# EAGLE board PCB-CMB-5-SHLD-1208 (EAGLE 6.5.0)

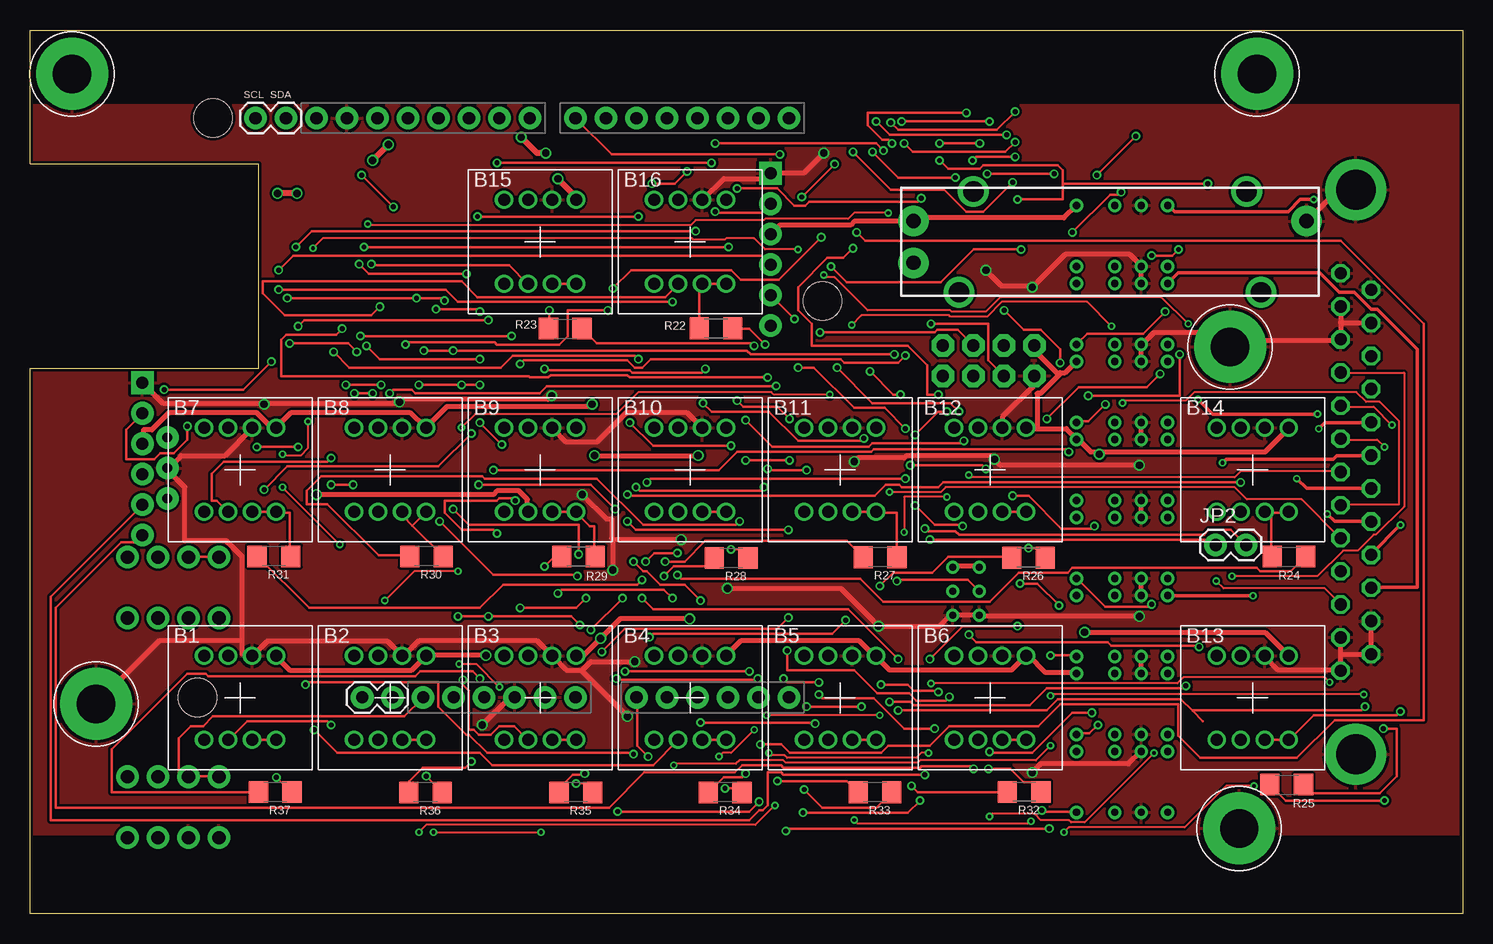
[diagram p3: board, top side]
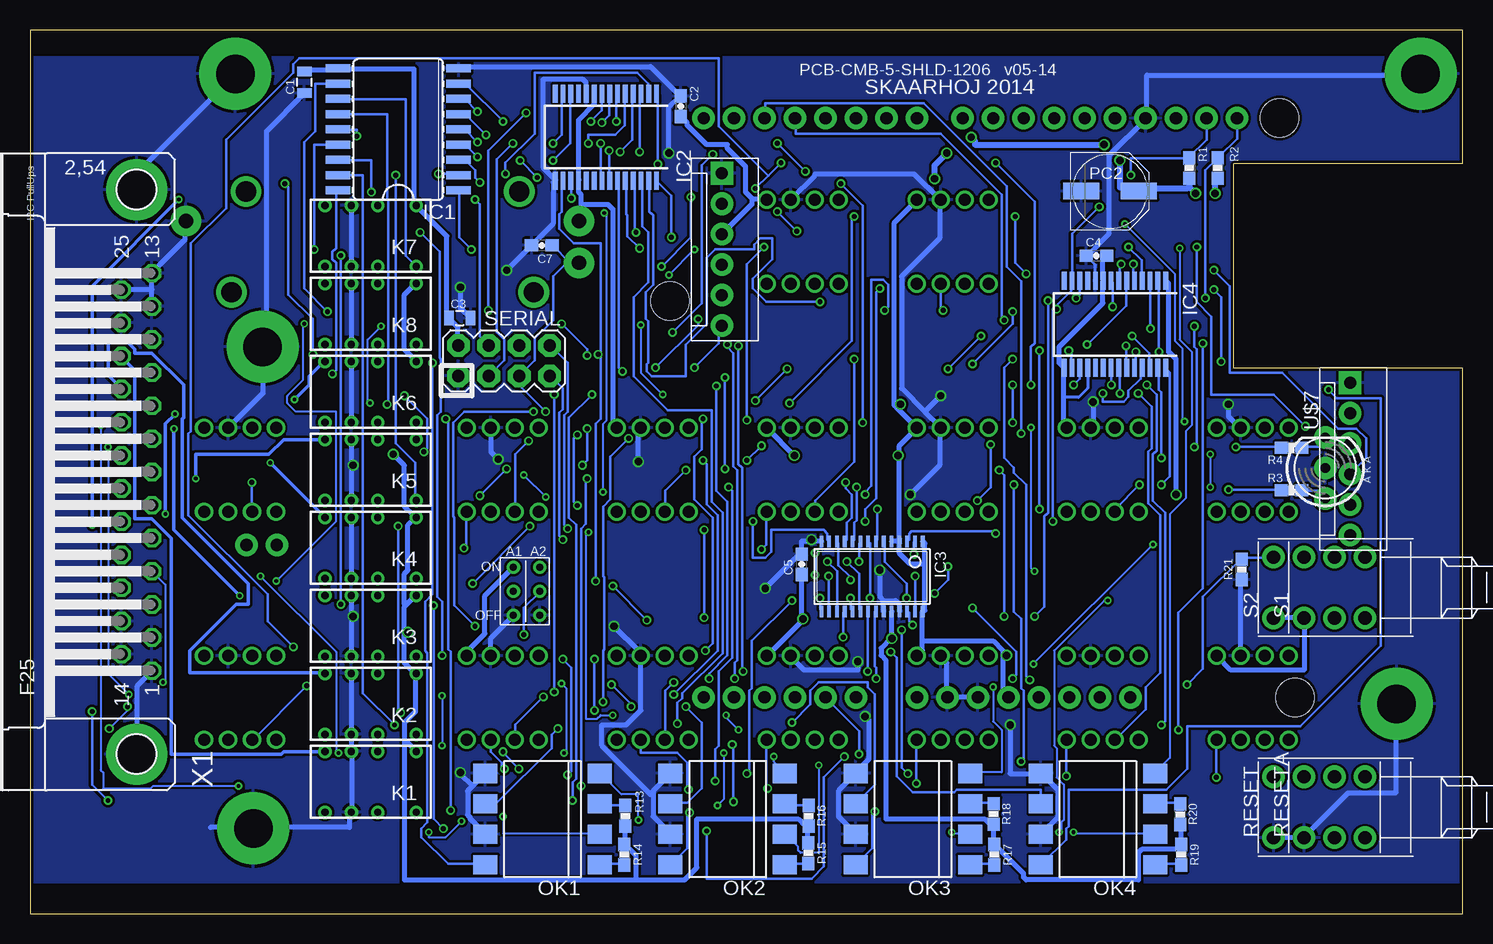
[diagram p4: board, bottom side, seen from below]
Size 119.38 x 73.66 mm. Coordinates in mm from the lower left corner, seen from the top.
Outline: 0,0 0,45.47 19.05,45.47 19.05,62.5 0,62.5 0,73.66 119.38,73.66 119.38,0 0,0
Copper layers (1*16): Top 0.035mm / dielectric 1.5mm / Bottom 0.035mm
Design rules "Fusion_eagle_rule_v1.1": minimum track width 6mil, minimum drill 12mil, track to track 6mil, track to pad 6mil, pad to pad 6mil, via to via 6mil, smd to smd 0mil, copper to edge 10mil, drill to drill 10mil, minimum pad ring 10mil, minimum via ring 6mil, stop-mask expansion 2mil, vias tented up to drill 100mil, thermal gap 10mil
Net classes: 0 default: width 0.203 mm, drill 0.406 mm, clearance 0.203 mm; 1 Power: width 0.508 mm, drill 0.61 mm, clearance 0.203 mm; 2 RELAY LINES: width 0.305 mm, clearance 0.203 mm; 3 INput lines: clearance 0.203 mm
Holes 3.2 mm at 66.04,51.07 15.24,66.31 13.97,18.05
tRestrict: area 0,0 to 120,6.5; area 0,67.5 to 120,74
bRestrict: area 0,71.5 to 120,74; area 0,0 to 120,2.5

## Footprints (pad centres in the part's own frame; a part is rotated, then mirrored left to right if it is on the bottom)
NKK-NP01 = drill 1: 1 1,3.5; 2 -1,-3.5; L1 3,-3.5; L2 1,-3.5; L3 -1,3.5; L4 -3,3.5; LC1 3,3.5; LC2 -3,-3.5
0805 = smd 0.8 x 1.2: 1 -0.9,0; 2 0.9,0
0603-CAP = smd 1.1 x 1: 1 -0.85,0; 2 0.85,0
DUEMILANOVE_VIAS = drill 1.016 pad 1.88: 3.3V 50.8,13.97; 5V 50.8,16.51; A0 50.8,29.21; A1 50.8,31.75; A2 50.8,34.29; A3 50.8,36.83; A4 50.8,39.37; A5 50.8,41.91; AREF 2.54,2.54; D2 2.54,36.83; D3 2.54,34.29; D4 2.54,31.75; D5 2.54,29.21; D6 2.54,26.67; D7 2.54,24.13; D8 2.54,20.32; D9 2.54,17.78; D10 2.54,15.24; D11 2.54,12.7; D12 2.54,10.16; D13 2.54,7.62; GND@0 50.8,19.05; GND@1 50.8,21.59; GND@2 2.54,5.08; RES 50.8,11.43; RX 2.54,41.91; TX 2.54,39.37; VIN 50.8,24.13
SO18W = smd 0.66 x 2.032: 1 -5.08,-5.029; 2 -3.81,-5.029; 3 -2.54,-5.029; 4 -1.27,-5.029; 5 0,-5.029; 6 1.27,-5.029; 7 2.54,-5.029; 8 3.81,-5.029; 9 5.08,-5.029; 10 5.08,5.029; 11 3.81,5.029; 12 2.54,5.029; 13 1.27,5.029; 14 0,5.029; 15 -1.27,5.029; 16 -2.54,5.029; 17 -3.81,5.029; 18 -5.08,5.029
SSOP28 = smd 0.4 x 1.5: 1 -4.225,-3.625; 2 -3.575,-3.625; 3 -2.925,-3.625; 4 -2.275,-3.625; 5 -1.625,-3.625; 6 -0.975,-3.625; 7 -0.325,-3.625; 8 0.325,-3.625; 9 0.975,-3.625; 10 1.625,-3.625; 11 2.275,-3.625; 12 2.925,-3.625; 13 3.575,-3.625; 14 4.225,-3.625; 15 4.225,3.625; 16 3.575,3.625; 17 2.925,3.625; 18 2.275,3.625; 19 1.625,3.625; 20 0.975,3.625; 21 0.325,3.625; 22 -0.325,3.625; 23 -0.975,3.625; 24 -1.625,3.625; 25 -2.275,3.625; 26 -2.925,3.625; 27 -3.575,3.625; 28 -4.225,3.625
TSSOP28 = smd 0.305 x 0.991: 1 -4.225,-2.918; 2 -3.575,-2.918; 3 -2.925,-2.918; 4 -2.275,-2.918; 5 -1.625,-2.918; 6 -0.975,-2.918; 7 -0.325,-2.918; 8 0.325,-2.918; 9 0.975,-2.918; 10 1.625,-2.918; 11 2.275,-2.918; 12 2.925,-2.918; 13 3.575,-2.918; 14 4.225,-2.918; 15 4.225,2.918; 16 3.575,2.918; 17 2.925,2.918; 18 2.275,2.918; 19 1.625,2.918; 20 0.975,2.918; 21 0.325,2.918; 22 -0.325,2.918; 23 -0.975,2.918; 24 -1.625,2.918; 25 -2.275,2.918; 26 -2.925,2.918; 27 -3.575,2.918; 28 -4.225,2.918
1X02 = drill 1.016 pad 1.88: 1 0,0; 2 2.54,0
MOLEX-1X6 = drill 1.016 pad 1.88 square: 1 0,0 | drill 1.016 pad 1.88: 2 2.54,0; 3 5.08,0; 4 7.62,0; 5 10.16,0; 6 12.7,0
DS2Y = drill 0.6: 1 1.2,0.46; 16 1.2,5.54; O1 4.4,0.46; O2 4.4,5.54; P1 6.6,0.46; P2 6.6,5.54; S1 8.8,0.46; S2 8.8,5.54
DIL8-SMD = smd 1.6 x 2: 1 -3.81,-4.77; 2 -1.27,-4.77; 3 1.27,-4.77; 4 3.81,-4.77; 5 3.81,4.77; 6 1.27,4.77; 7 -1.27,4.77; 8 -3.81,4.77
PANASONIC_D = smd 3 x 1.4: + 2.4,0; - -2.4,0
SLIDER20 = drill 1.194 pad 2.54: 1 -16.383,1.74; 2A -16.383,-1.74; 3 16.383,1.74 | drill 1.702: P$1 -11.392,4.191; P$2 11.392,4.191; P$3 12.598,-4.191; P$4 -12.598,-4.191
0603-RES = smd 1.1 x 1: 1 -0.85,0; 2 0.85,0
1206 = smd 1.6 x 1.8: 1 -1.4,0; 2 1.4,0
PUSHBUTTON = drill 1.1 pad 1.88: 1 2.54,2.54; 2 2.54,-2.54; 3 -2.54,2.54; 4 -2.54,-2.54
2X4 = drill 1.016 pad 1.88 octagon: 1 -3.81,-1.27; 2 -3.81,1.27; 3 -1.27,-1.27; 4 -1.27,1.27; 5 1.27,-1.27; 6 1.27,1.27; 7 3.81,-1.27; 8 3.81,1.27
3.2MMPAD6MM = drill 3.2 pad 6: P$1 0,0
LED5MM-BICOLOR = drill 0.813 pad 1.88: A2 2.54,0; A3 -2.54,0; K1 0,0
2BITADDR = drill 0.6: A1 0,0; A2 2.2,0; H2 0,2; H3 2.2,2; L2 0,-2; L3 2.2,-2
F25HP = drill 1.016 octagon: 1 -16.561,-1.27; 2 -13.792,-1.27; 3 -11.049,-1.27; 4 -8.28,-1.27; 5 -5.512,-1.27; 6 -2.769,-1.27; 7 0,-1.27; 8 2.769,-1.27; 9 5.512,-1.27; 10 8.28,-1.27; 11 11.049,-1.27; 12 13.792,-1.27; 13 16.561,-1.27; 14 -15.189,1.27; 15 -12.421,1.27; 16 -9.652,1.27; 17 -6.909,1.27; 18 -4.14,1.27; 19 -1.372,1.27; 20 1.372,1.27; 21 4.14,1.27; 22 6.909,1.27; 23 9.652,1.27; 24 12.421,1.27; 25 15.189,1.27 | drill 3.302 pad 5.08: G1 -23.52,0; G2 23.52,0

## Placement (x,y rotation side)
B1  NKK-NP01-SINGLECOLOR  [NKK-NP01]  17.5,18 0 top
B2  NKK-NP01-SINGLECOLOR  [NKK-NP01]  30,18 0 top
B3  NKK-NP01-SINGLECOLOR  [NKK-NP01]  42.5,18 0 top
B4  NKK-NP01-SINGLECOLOR  [NKK-NP01]  55,18 0 top
B5  NKK-NP01-SINGLECOLOR  [NKK-NP01]  67.5,18 0 top
B6  NKK-NP01-SINGLECOLOR  [NKK-NP01]  80,18 0 top
B7  NKK-NP01-SINGLECOLOR  [NKK-NP01]  17.5,37 0 top
B8  NKK-NP01-SINGLECOLOR  [NKK-NP01]  30,37 0 top
B9  NKK-NP01-SINGLECOLOR  [NKK-NP01]  42.5,37 0 top
B10  NKK-NP01-SINGLECOLOR  [NKK-NP01]  55,37 0 top
B11  NKK-NP01-SINGLECOLOR  [NKK-NP01]  67.5,37 0 top
B12  NKK-NP01-SINGLECOLOR  [NKK-NP01]  80,37 0 top
B13  NKK-NP01-SINGLECOLOR  [NKK-NP01]  101.88,18 0 top
B14  NKK-NP01-SINGLECOLOR  [NKK-NP01]  101.88,37 0 top
B15  NKK-NP01-SINGLECOLOR  [NKK-NP01]  42.5,56 0 top
B16  NKK-NP01-SINGLECOLOR  [NKK-NP01]  55,56 0 top
C1  100nF  [0805]  96.52,69.31 90 bottom
C2  100nF  [0603-CAP]  65.15,67.31 270 bottom
C3  10uF  [0805]  83.57,49.66 0 bottom
C4  100nF  [0603-CAP]  30.51,54.86 0 bottom
C5  100nF  [0603-CAP]  55.07,29.13 90 bottom
C7  10nF  [0603-CAP]  76.73,55.71 180 bottom
GND  ARDUINO_SHIELDNO_SILK  [DUEMILANOVE_VIAS]  21.34,68.85 270 top
IC1  ULN2803A  [SO18W]  88.7,65.38 90 bottom
IC2  MCP23017SS  [SSOP28]  71.39,64.73 180 bottom
IC3  PCA9685  [TSSOP28]  49.21,28.12 180 bottom
IC4  MCP23017SS  [SSOP28]  28.97,49.12 180 bottom
JP1  [1X02]  27.69,18.05 0 top
JP2  [1X02]  98.81,30.75 0 top
JP3  [MOLEX-1X6]  61.72,61.72 270 bottom
JP4  [1X02]  21.34,66.31 180 top
JP5  [MOLEX-1X6]  9.36,44.26 270 bottom
K1  RELAY5VIM03  [DS2Y]  86,14 180 bottom
K2  RELAY5VIM03  [DS2Y]  86,20.5 180 bottom
K3  RELAY5VIM03  [DS2Y]  86,27 180 bottom
K4  RELAY5VIM03  [DS2Y]  86,33.5 180 bottom
K5  RELAY5VIM03  [DS2Y]  86,40 180 bottom
K6  RELAY5VIM03  [DS2Y]  86,46.5 180 bottom
K7  RELAY5VIM03  [DS2Y]  86,59.5 180 bottom
K8  RELAY5VIM03  [DS2Y]  86,53 180 bottom
OK1  LTV826S  [DIL8-SMD]  76.67,7.9 90 bottom
OK2  LTV826S  [DIL8-SMD]  61.24,7.9 90 bottom
OK3  LTV826S  [DIL8-SMD]  45.81,7.9 90 bottom
OK4  LTV826S  [DIL8-SMD]  30.38,7.9 90 bottom
PC2  47u  [PANASONIC_D]  29.38,60.24 0 bottom
POT1  10K Linear  [SLIDER20]  90,56 0 top
R1  1K5  [0603-RES]  22.77,62.15 270 bottom
R2  1K5  [0603-RES]  20.4,62.15 270 bottom
R3  270  [0603-RES]  14.24,35.29 180 bottom
R4  270  [0603-RES]  14.24,38.83 180 bottom
R13  330R  [0603-RES]  69.76,8.18 90 bottom
R14  330R  [0603-RES]  69.86,4.93 270 bottom
R15  330R  [0603-RES]  54.53,5.06 270 bottom
R16  330R  [0603-RES]  54.47,8.18 90 bottom
R17  330R  [0603-RES]  39.03,4.93 270 bottom
R18  330R  [0603-RES]  39.06,8.32 90 bottom
R19  330R  [0603-RES]  23.46,4.93 270 bottom
R20  330R  [0603-RES]  23.52,8.3 90 bottom
R21  10K  [0603-RES]  18.41,28.72 90 bottom
R22  100R  [1206]  57.16,48.8 0 top
R23  100R  [1206]  44.61,48.77 0 top
R24  100R  [1206]  104.91,29.77 0 top
R25  100R  [1206]  104.72,10.77 0 top
R26  100R  [1206]  83.2,29.68 180 top
R27  100R  [1206]  70.84,29.72 180 top
R28  100R  [1206]  58.43,29.65 180 top
R29  100R  [1206]  45.71,29.78 180 top
R30  100R  [1206]  33.04,29.8 180 top
R31  100R  [1206]  20.32,29.8 180 top
R32  100R  [1206]  82.84,10.16 180 top
R33  100R  [1206]  70.41,10.14 180 top
R34  100R  [1206]  57.93,10.12 180 top
R35  100R  [1206]  45.48,10.12 180 top
R36  100R  [1206]  32.96,10.12 180 top
R37  100R  [1206]  20.43,10.15 180 top
RESET  [PUSHBUTTON]  13.21,8.89 90 bottom
RESETA  [PUSHBUTTON]  10.67,8.89 90 bottom
S1  [PUSHBUTTON]  10.67,27.19 90 bottom
S2  [PUSHBUTTON]  13.21,27.19 90 bottom
SERIAL  M04X2  [2X4]  79.88,46.1 0 bottom
U$4  GNDPAD6MM  [3.2MMPAD6MM]  100,47.25 0 top
U$7  LEDBICOLOR-AKA  [LED5MM-BICOLOR]  11.44,37.16 90 bottom
U$15  GNDPAD6MM  [3.2MMPAD6MM]  100.77,7.12 0 top
U$18  GNDPAD6MM  [3.2MMPAD6MM]  102.26,70 0 top
U$19  2BITADDR  [2BITADDR]  79.1,26.89 0 bottom
U$20  GNDPAD6MM  [3.2MMPAD6MM]  5.5,17.5 0 top
U$21  GNDPAD6MM  [3.2MMPAD6MM]  3.5,70 0 top
X1  DB25F  [F25HP]  110.49,36.83 90 bottom

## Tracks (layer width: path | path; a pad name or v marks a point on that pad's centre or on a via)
5V  (via drill 0.61)
  Top 0.406: JP5.3 9.45,39.22 9.45,40.34 10.16,40.34 11.58,41.76 18.9,41.76 20.12,40.54 20.32,40.54 B7.LC1 20.52,40.54 21.74,41.76 31.7,41.76 32.92,40.54 B8.LC1 33.12,40.64 34.75,42.27 46.63,42.27 v46.84,42.47 | B1.LC1 20.52,21.44 21.64,20.32 31.8,20.32 32.92,21.44 B2.LC1 33.12,21.54 v38,21.54 | B3.LC1 45.52,21.54 46.13,21.54 v47.55,22.96 49.17,24.59 v54.97,24.59 | v47.04,38.2 v55.68,38.2 | JP3.3 62.48,57.4 68.38,57.4 68.68,57.71 73.56,57.71 POT1.1 73.76,57.81 73.97,58.01 86.16,58.01 87.17,59.03 K7.1 | 83.92,40.44 83.01,40.44 B12.LC1 | 83.92,40.44 86.36,40.44 87.17,39.62 K5.1 87.38,39.52 88.39,38.51 89.1,38.51 | 89.1,38.51 102.92,38.51 104.85,40.44 B14.LC1 | 85.85,45.11 85.55,45.11 83.72,46.94 83.72,47.35 SERIAL.2 | 85.85,45.11 86.26,45.11 87.17,46.02 K6.1 | 83.92,40.44 83.92,43.38 84.23,43.38 85.85,45.01 85.85,45.11 | U$19.H3 76.91,28.96 79.05,28.96 U$19.H2 | B4.LC1 58.01,21.54 59.23,22.76 69.09,22.76 70.31,21.54 B5.LC1 70.51,21.44 71.63,20.32 81.79,20.32 82.91,21.44 B6.LC1 83.21,21.54 84.63,20.12 87.17,20.12 K2.1 | v87.88,23.47 102.92,23.47 104.85,21.54 B13.LC1 | v89.1,38.3 89.1,38.51
  Top 0.508: v22.25,60.05 v20.62,60.05 | v29.87,64.11 v28.55,62.79 | v40.95,64.72 42.27,63.4 v42.98,63.4 | v43.99,61.27 45.41,59.84 45.41,59.54 B15.LC1
  Bottom 0.254: IC4.18 31.24,43.81 32,43.05 33.22,43.05
  Bottom 0.406: C4.2 29.67,54.76 29.97,54.46 29.97,52.83 IC4.9 29.97,52.63 29.97,50.9 33.63,47.24 33.63,45.92 33.33,45.62 IC4.15 33.22,45.41 33.22,43.05 33.22,40.74 33.02,40.54 B8.LC1 | B1.LC1 20.42,21.44 19.3,20.32 13.21,20.32 S1.3 13.31,24.69 15.75,24.69 S2.3 | R20.1 23.47,7.42 23.47,5.79 R19.1 23.47,5.59 23.47,5.38 26.72,5.38 27.03,5.08 27.03,2.85 36.37,2.85 36.58,3.05 36.58,3.35 38.91,5.69 R17.1 39.12,5.79 39.12,7.42 R18.1 39.32,7.42 39.83,7.92 48.06,7.92 48.06,21.13 48.46,21.54 48.46,22.15 47.65,22.96 v47.55,22.96 47.55,25.2 IC3.24 | IC3.4 46.94,31.09 47.55,31.09 IC3.5 | 45.01,22.76 45.01,21.95 45.41,21.54 B3.LC1 | 45.01,22.76 45.01,25.2 IC3.28 44.81,25.3 44.81,29.16 | 44.81,29.16 44.81,30.89 44.91,30.99 IC3.1 | 44.81,29.16 46.02,29.16 46.94,30.07 46.94,30.89 IC3.4 | 46.94,38.2 46.94,31.29 IC3.4 | 46.94,38.2 46.94,39.01 45.52,40.44 B9.LC1 45.62,40.64 47.14,42.16 | v55.68,38.2 57.91,40.44 B10.LC1 | v47.04,38.2 46.94,38.2 | 47.14,42.16 47.35,42.37 47.35,57.61 45.52,59.44 B15.LC1 | 38.3,21.54 38.3,21.95 39.12,22.76 45.01,22.76 | 38.3,21.54 38.3,18.49 37.9,18.09 GND.5V | 38.3,21.54 v38,21.54 | 47.14,42.16 v46.84,42.47 | 59.13,59.54 59.74,60.15 59.74,62.28 61.27,63.8 61.27,64.11 62.99,64.11 64.62,65.73 64.62,65.94 65.13,66.45 C2.2 | 59.13,59.54 58.01,59.54 B16.LC1 | JP3.3 59.23,59.13 59.23,59.44 59.13,59.54 | 73.46,59.13 73.46,57.91 73.56,57.81 POT1.1 | 73.46,59.13 73.46,59.94 73.66,60.15 73.66,61.06 IC2.18 73.66,61.27 73.66,66.14 72.34,67.46 72.34,68.28 IC2.9 | 73.46,59.13 71.22,59.13 70.81,58.73 70.81,40.84 70.51,40.54 B11.LC1 | C1.2 96.52,70.31 93.78,70.31 93.78,70.41 IC1.10 93.57,70.41 87.38,70.41 87.38,59.13 K7.1 87.17,59.03 84.63,56.49 84.63,49.78 C3.1 84.43,49.58 83.72,48.87 83.72,47.45 SERIAL.2
  Bottom 0.406: K8.1 87.27,52.53 88.19,51.61 88.19,47.04 87.27,46.13 K6.1 | 55.07,24.59 55.07,24.38 57.91,21.54 B4.LC1 | 55.07,24.59 55.07,28.25 C5.1 | U$19.H2 79.15,28.85 81.48,26.52 81.48,23.37 82.91,21.95 82.91,21.54 B6.LC1 | R15.1 54.56,5.99 54.56,7.32 R16.1 54.76,7.32 55.37,7.92 63.8,7.92 63.8,3.86 64.82,2.85 68.89,2.85 | R13.1 69.8,7.32 69.8,5.79 R14.1 69.7,5.69 68.89,4.88 68.89,2.85 | 88.09,14.43 88.19,14.53 88.19,15.95 87.27,16.87 87.27,20.02 K2.1 87.38,20.12 88.19,20.93 88.19,23.47 | 88.09,14.43 K1.1 | 88.09,25.7 88.19,25.6 88.19,23.47 | 88.09,25.7 87.27,26.52 K3.1 | 88.09,25.7 88.19,25.81 88.19,28.35 87.88,28.65 87.88,32.41 87.27,33.02 K4.1 87.38,33.12 88.19,33.93 88.19,37.39 v89.1,38.3 | 88.19,23.47 v87.88,23.47 | 68.89,2.85 88.19,2.85 88.19,14.33 88.09,14.43 | v54.97,24.59 55.07,24.59
  Bottom 0.508: v20.62,60.05 20.62,61.06 20.42,61.27 R2.2 | 22.76,60.55 v22.25,60.05 | 22.76,60.55 22.76,61.27 R1.2 | 22.76,60.55 22.96,60.45 26.92,60.45 26.92,60.25 PC2.+ 27.13,60.55 28.55,60.55 v28.55,62.79 | v29.87,64.11 40.64,64.11 40.64,64.41 v40.95,64.72 | v42.98,63.4 43.99,62.38 v43.99,61.27
A1  (via drill 0.41)
  Top 0.203: v45.72,29.97 45.72,32.41 36.58,32.41 v35.26,33.73 | v32.82,46.94 v35.26,46.94 59.74,46.94 60.05,46.63 v72.03,46.63 | v72.24,27.74 72.34,27.84 78.13,27.84 79.05,26.92 U$19.A1
  Bottom 0.203: v45.72,29.97 45.72,30.99 IC3.2 | v35.26,46.94 v35.26,33.73 | v32.82,46.94 32.61,46.74 32.61,45.52 IC4.16 | 71.83,46.63 71.83,41.25 72.24,40.84 v72.24,27.74 | 71.83,46.63 71.83,55.88 74.07,55.88 75.29,57.1 75.29,58.32 75.08,58.52 75.08,60.96 74.98,61.06 IC2.16 | 71.83,46.63 v72.03,46.63
A1CFG  (via drill 0.41)
  Top 0.203: v50.29,13.31 50.19,13.41 38.1,13.41 36.58,14.94 36.37,14.94 34.04,17.27 34.04,19.3 23.16,19.3 v22.96,19.1 | S1.1 13.21,29.77 15.75,29.77 S2.1
  Bottom 0.203: S2.1 15.75,29.67 18.39,29.67 R21.2 18.49,29.57 21.64,26.42 21.64,20.42 v22.96,19.1 | v50.29,13.31 50.29,15.24 53.03,17.98 GND.A1
A2  (via drill 0.41)
  Top 0.203: v38.91,31.7 38.61,32 35.97,32 34.54,33.43 34.54,34.44 38.91,34.44 39.12,34.65 40.23,34.65 v40.44,34.44 | v37.49,40.95 v39.32,39.12 | v32.41,44.09 v35.97,44.09 v37.49,44.09 | v74.27,59.64 73.97,59.33 64.92,59.33 64.62,59.03 63.7,59.03 62.28,60.45 v58.93,60.45 | v38.91,62.59 v56.79,62.59 | v78.23,23.27 78.84,22.66 89.81,22.66 90.12,22.35 97.33,22.35 v97.43,22.25
  Bottom 0.203: v38.91,31.7 38.91,31.9 45.92,31.9 46.13,31.7 46.13,31.19 46.23,31.09 IC3.3 | v40.44,34.44 39.32,35.56 v39.32,39.12 | v37.49,44.09 v37.49,40.95 | v32.41,44.09 31.9,44.6 31.9,45.41 IC4.17 | v74.27,59.64 74.27,61.06 IC2.17 | v56.79,62.59 57.86,61.52 | 57.86,61.52 v58.93,60.45 | v38.91,62.59 35.66,59.33 35.66,47.55 35.97,47.24 v35.97,44.09 | v78.23,23.27 78.23,25.5 76.91,26.82 U$19.A2 | v97.43,22.25 99.57,24.38 99.57,26.62 106.17,33.22 106.17,40.03 105.97,40.23 105.97,55.88 103.02,58.83 103.02,64.52 97.43,70.1 97.43,70.81 96.93,71.32 61.98,71.32 61.98,65.63 57.86,61.52
D2  (via drill 0.41)
  Top 0.203: v19.51,35.36 21.44,37.29 34.04,37.29 v36.78,40.03
  Bottom 0.203: v19.51,35.36 15.14,35.36 R3.2 | v36.78,40.03 36.78,52.73 38,53.95 38,60.66 44.91,67.56 58.12,67.56 58.12,66.34 GND.D2
D3  (via drill 0.41)
  Top 0.203: v22.35,38.91 v18.9,38.91 | v22.35,48.97 22.86,49.48 v38.2,49.48
  Bottom 0.203: v18.9,38.91 15.14,38.91 R4.2 | v22.35,38.91 22.15,39.12 22.15,47.04 22.35,47.24 v22.35,48.97 | v38.2,49.48 38.41,49.68 38.41,59.94 43.48,65.02 55.58,65.02 55.58,66.24 GND.D3
DISP_DATA_OUT  (via drill 0.41)
  Top 0.203: v62.48,63.3 48.46,63.3 45.52,66.24 GND.D7 | v65.84,48.46 75.39,48.46 75.59,48.67 77.32,48.67 78.54,47.45 SERIAL.6
  Bottom 0.203: v62.48,63.3 63.4,62.38 63.4,50.9 v65.84,48.46
GND  (via drill 0.61)
  Top 0.406: X1.12 109.22,49.28 | 109.22,49.28 X1.11 109.12,47.75 100.48,47.75 100.08,47.35 U$4.P$1 99.87,47.35 98.75,48.46 93.67,48.46 92.76,47.55 K8.P2 92.56,47.45 92.56,46.13 K6.P1 | 109.22,49.28 111.76,49.28 X1.24 | X1.G2 109.02,60.35 106.48,57.81 POT1.3 | K8.P1 92.56,52.63 92.56,53.85 K7.P2 92.56,54.05 91.64,54.97 86.26,54.97 v83.52,52.22 83.41,52.32 80.97,52.32 v79.65,53.65 | B13.1 102.92,21.44 104.04,20.32 109.22,20.32 X1.1 109.22,21.64 | 109.22,21.64 X1.2 | 109.22,21.64 X1.14 X1.15 | v68.68,37.69 68.99,38 72.85,38 73.05,38.2 80.06,38.2 v80.37,37.9 80.87,37.39 v92.46,37.39 | SERIAL.1 83.62,44.81 83.62,43.99 81.08,41.45 81.08,40.54 B12.1 | K5.P1 92.56,39.62 92.56,40.95 K6.P2 | K4.P1 92.56,33.12 92.56,34.44 K5.P2 | K3.P1 92.56,26.62 92.56,27.94 K4.P2 | K2.P1 92.56,20.12 92.56,21.44 K3.P2 | v83.52,11.79 84.23,12.5 91.54,12.5 92.56,13.51 K1.P1 | v92.46,24.79 79.25,24.79 U$19.L2 79.05,24.89 76.91,24.89 U$19.L3 76.71,24.89 75.79,23.98 v70.71,23.98 67.56,27.13 v58.12,27.13 | B7.1 18.49,40.44 16.26,38.2 12.6,38.2 11.58,37.19 11.48,37.19 U$7.K1 11.48,36.98 12.9,35.56 12.9,31.09 16.36,31.09 17.68,29.77 17.68,22.76 | 19.51,42.57 11.07,42.57 9.45,44.2 JP5.1 | 19.51,42.57 30.68,42.57 v30.79,42.67 30.99,42.88 43.18,42.88 v43.48,43.18 | v19.51,42.47 19.51,42.57 | v37.69,15.75 39.93,17.98 40.34,17.98 GND.GND@0 | v50.39,21.03 46.74,21.03 46.02,20.32 | 46.02,20.32 44.7,20.32 43.59,21.44 B3.1 43.38,21.64 42.27,22.76 32.41,22.76 31.19,21.54 B2.1 30.99,21.54 29.77,22.76 19.81,22.76 18.59,21.54 B1.1 18.39,21.64 17.68,21.64 17.68,22.76 | v49.78,16.46 46.02,20.22 46.02,20.32
  Top 0.406: 17.68,22.76 10.77,22.76 5.59,17.58 U$20.P$1 | 48.56,31.19 v48.56,28.65 | v54.25,31.19 48.56,31.19 | B9.1 43.59,40.44 44.7,39.32 47.24,39.32 49.68,41.76 54.76,41.76 55.98,40.54 B10.1 | v46.02,34.95 48.06,32.92 48.46,32.92 48.46,31.29 48.56,31.19 | B16.1 56.08,59.54 57.81,61.27 61.27,61.27 JP3.1 61.87,61.77 64.52,61.77 v66.14,63.4
  Bottom 0.254: IC4.10 30.59,54.09 C4.1
  Bottom 0.406: C1.1 96.52,68.38 99.67,65.23 99.67,47.65 99.97,47.35 U$4.P$1 99.97,47.04 99.97,43.38 102.82,40.54 B14.1 | X1.12 109.22,52.02 | 109.22,52.02 X1.13 109.12,53.54 106.48,56.19 106.48,57.71 POT1.3 | 109.22,52.02 X1.25 | U$18.P$1 102.31,69.9 110.44,61.77 110.44,60.35 X1.G2 | IC2.10 73.05,68.38 73.05,69.29 73.36,69.6 76.61,69.6 76.61,62.18 75.69,61.27 IC2.15 75.69,61.06 75.79,60.96 75.79,57.51 77.52,55.78 C7.2 77.72,55.58 v79.65,53.65 | v83.52,52.22 83.52,50.49 82.7,49.68 C3.2 | K7.P1 92.56,59.03 92.56,54.05 K7.P2 | U$19.L2 79.15,24.79 80.97,22.96 80.97,21.54 B6.1 | 67.46,9.86 67.46,10.26 66.04,11.68 OK2.5 | 67.46,9.86 67.46,8.13 66.04,6.71 OK2.7 | 67.46,9.86 67.56,9.86 71.73,14.02 71.73,15.75 69.7,15.75 68.48,16.97 68.48,21.44 B5.1 68.58,21.64 68.58,21.84 v70.71,23.98 | X1.1 109.22,20.22 110.44,19 110.44,13.31 X1.G1 110.34,13.21 | v68.68,37.69 68.68,40.34 68.58,40.44 B11.1 | v80.37,37.9 80.97,38.51 80.97,40.44 B12.1 | 82.5,10.67 81.48,11.68 OK1.5 | 82.5,10.67 82.91,10.26 82.91,8.23 82.7,8.03 82.7,7.92 81.48,6.71 OK1.7 | K2.P1 92.56,20.02 92.56,15.14 K2.P2 92.56,14.94 92.56,13.72 K1.P1 92.56,13.51 92.56,8.53 K1.P2 92.76,8.33 92.76,7.21 100.69,7.21 U$15.P$1 100.89,7.21 104.34,7.21 | 92.56,24.79 92.56,21.54 K3.P2 | 92.56,24.79 92.56,26.52 K3.P1 | K4.P1 92.56,33.02 92.56,28.04 K4.P2 | 92.56,37.39 92.56,34.54 K5.P2 | 92.56,37.39 92.56,39.52 K5.P1 | K6.P1 92.56,46.02 92.56,41.05 K6.P2 | 82.5,10.67 83.52,11.68 v83.52,11.79 | v92.46,37.39 92.56,37.39 | v92.46,24.79 92.56,24.79 | K8.P1 92.56,52.53 92.56,47.55 K8.P2 | RESET.3 15.75,6.4 13.21,6.4 RESETA.3 13.11,6.5 9.55,10.06 5.59,10.06 5.59,17.48 U$20.P$1
  Bottom 0.406: v30.79,42.67 30.79,40.74 30.99,40.54 B8.1 | v19.51,42.47 19.51,41.45 18.59,40.54 B7.1 | R21.1 18.49,27.84 18.49,21.54 B1.1 | OK4.7 35.05,6.71 33.73,8.03 33.73,10.36 35.05,11.68 OK4.5 35.36,11.68 37.69,11.68 v37.69,15.75 | OK3.7 50.6,6.71 52.02,8.13 52.02,10.26 50.6,11.68 OK3.5 50.49,11.89 49.48,12.9 49.48,16.15 v49.78,16.46 | B3.1 43.48,21.44 42.98,20.93 42.98,18.09 GND.GND@1 42.77,18.09 40.44,18.09 GND.GND@0 | v50.39,21.03 50.39,20.32 54.86,20.32 55.98,21.44 B4.1 | 48.26,26.11 47.24,26.11 46.94,25.81 46.94,25.3 IC3.25 | 48.26,26.11 48.26,25.3 IC3.23 | IC3.14 53.44,31.09 54.25,31.09 | 54.25,31.09 55.07,31.09 55.07,30.07 C5.2 55.27,29.97 v58.12,27.13 | 48.26,26.11 48.56,26.42 v48.56,28.65 | v54.25,31.19 54.25,31.09 | v46.02,34.95 43.59,37.39 43.59,40.44 B9.1 43.59,40.64 44.81,41.86 | IC1.9 83.62,70.51 83.62,70.61 67.67,70.61 65.23,68.17 C2.1 65.33,68.07 66.14,67.26 v66.14,63.4 | C4.1 31.29,54.86 29.46,56.69 29.46,63.2 26.42,66.24 GND.GND@2 26.31,66.45 26.31,69.9 3.56,69.9 U$21.P$1 | B16.1 55.98,59.54 53.95,61.57 53.95,61.67 45.72,61.67 43.59,59.54 B15.1 43.59,59.33 43.59,56.29 46.74,53.14 46.74,43.79 44.81,41.86 | 44.81,41.86 v43.48,43.18
  pour Top: 0,0 119,0 119,74 0,74
  pour Bottom: 0,0 119,0 119,74 0,74
GPA0  (via drill 0.41)
  Top 0.203: v26.31,44.09 v29.26,44.09 | v25.09,15.75 24.79,16.05 18.09,16.05 16.56,14.53 B1.2
  Bottom 0.203: v29.26,44.09 29.26,45.41 IC4.21 | v26.31,44.09 25.5,43.28 25.5,38.61 25.81,38.3 25.81,34.44 24.79,33.43 24.79,16.05 v25.09,15.75
GPA1  (via drill 0.41)
  Top 0.203: v27.03,43.38 v28.55,43.38
  Bottom 0.203: v28.55,43.38 28.55,45.41 IC4.22 | v27.03,43.38 25.91,42.27 25.91,38.81 26.21,38.51 26.21,34.24 25.2,33.22 25.2,20.12 26.42,18.9 26.42,17.07 28.96,14.53 B2.2
GPA2  (via drill 0.41)
  Top 0.203: v28.04,47.35 29.16,46.23 v37.49,46.23 | v36.07,19.51 36.07,19.1 36.58,18.59 36.58,15.34 36.98,15.34 37.39,14.94 38.41,14.94 39.12,15.65 40.34,15.65 41.45,14.53 B3.2
  Bottom 0.203: v28.04,47.35 28.04,45.52 IC4.23 | v37.49,46.23 38.2,45.52 38.2,38 37.39,37.19 37.39,36.78 36.37,35.76 36.37,19.81 v36.07,19.51
GPA3  (via drill 0.41)
  Top 0.203: v27.23,46.84 26.52,47.55 v21.64,47.55 | v23.67,15.34 25.6,13.41 37.49,13.41 38.51,12.39 51.92,12.39 53.95,14.43 B4.2
  Bottom 0.203: v27.23,46.84 27.23,45.62 27.33,45.52 IC4.24 | v21.64,47.55 21.64,27.13 23.67,25.09 v23.67,15.34
GPA4  (via drill 0.41)
  Top 0.203: v29.97,43.38 30.28,43.69 31.8,43.69 32.11,43.38 42.47,43.38 43.08,43.99 v62.18,43.99 | v62.79,19.61 63.09,19.3 v65.73,19.3
  Bottom 0.203: v29.97,43.38 29.97,42.67 28.25,42.67 27.84,43.08 27.84,43.59 26.82,44.6 26.82,45.31 26.72,45.41 IC4.25 | v62.18,43.99 62.18,35.26 61.27,34.34 61.27,21.54 62.79,20.02 v62.79,19.61 | v65.73,19.3 66.45,18.59 66.45,14.53 B5.2
GPA5  (via drill 0.41)
  Top 0.203: v40.13,48.16 v27.53,48.16 | v42.88,45.41 42.98,45.31 49.99,45.31 50.19,45.11 55.98,45.11 v56.29,45.41 | v58.93,42.77 59.44,42.27 62.28,42.27 v63.3,41.25 | v63.09,21.95 63.09,20.32 68.68,20.32 70.61,18.39 73.25,18.39 73.86,17.78 76.3,17.78 v76.61,18.09
  Bottom 0.203: v27.53,48.16 26.11,46.74 26.11,45.52 IC4.26 | v42.88,45.41 v40.13,48.16 | v58.93,42.77 v56.29,45.41 | v63.3,41.25 63.4,41.15 63.4,38.71 64.01,38.1 64.01,34.54 62.48,33.02 62.48,22.55 v63.09,21.95 | v76.61,18.09 78.94,15.75 78.94,14.53 B6.2
GPA6  (via drill 0.41)
  Top 0.203: v25.09,38 24.79,37.69 16.15,37.69 15.14,36.68 15.14,34.44 15.54,34.44 16.46,33.53 B7.2
  Bottom 0.203: v25.09,38 25.09,43.48 25.3,43.69 25.3,45.41 IC4.27
GPA7  (via drill 0.41)
  Top 0.203: v26.92,35.76 v25.09,35.76
  Bottom 0.203: v25.09,35.76 24.38,36.47 24.38,45.11 24.69,45.41 IC4.28 | v26.92,35.76 28.96,33.73 28.96,33.53 B8.2
GPB0  (via drill 0.61)
  Top 0.406: v23.88,34.95 38.61,34.95 38.91,35.26 40.74,35.26 41.45,34.54 41.45,33.53 B9.2
  Bottom 0.406: v23.88,34.95 23.88,46.23 24.49,46.84 24.49,52.53 24.69,52.73 IC4.1
GPB1  (via drill 0.41)
  Top 0.203: v25.3,46.84 26.62,45.52 39.22,45.52 40.23,46.53 50.39,46.53 v50.7,46.23
  Bottom 0.203: v25.3,46.84 25.3,52.73 IC4.2 | v50.7,46.23 50.7,37.69 53.95,34.44 53.95,33.53 B10.2
GPB2  (via drill 0.41)
  Top 0.203: v26.01,48.77 25.5,48.26 21.34,48.26 20.93,47.85 20.93,44.81 41.55,44.81 41.66,44.7 43.18,44.7 43.38,44.91 49.78,44.91 49.99,44.7 v61.47,44.7 | v61.47,37.08 61.57,36.98 v64.72,36.98
  Bottom 0.203: v26.01,48.77 26.01,52.73 IC4.3 | v61.47,37.08 v61.47,44.7 | v64.72,36.98 66.45,35.26 66.45,33.53 B11.2
GPB3  (via drill 0.41)
  Top 0.203: v58.22,55.58 v27.84,55.58 | v59.64,41.15 61.87,38.91 69.9,38.91 70.21,39.22 77.62,39.22 v77.83,39.42
  Bottom 0.203: v27.84,55.58 26.72,54.46 26.72,52.83 IC4.4 | v58.22,55.58 59.64,54.15 v59.64,41.15 | v77.83,39.42 78.94,38.3 78.94,33.53 B12.2
GPB4  (via drill 0.41)
  Top 0.203: v27.43,54.15 28.25,53.34 v36.37,53.34 | v50.7,58.12 v37.29,58.12 | v56.08,42.57 56.79,41.86 61.57,41.86 64.01,39.42 69.29,39.42 v69.49,39.62 | v71.63,17.68 73.36,17.68 73.66,17.37 83.31,17.37 84.73,18.8 96.11,18.8 v96.32,19
  Bottom 0.203: v27.43,54.15 27.43,52.83 IC4.5 | v36.37,53.34 37.29,54.25 v37.29,58.12 | v50.7,58.12 50.9,57.91 50.9,47.75 v56.08,42.57 | v69.49,39.62 71.02,38.1 71.02,34.54 71.63,33.93 71.63,28.14 71.53,28.04 71.53,22.05 71.63,21.95 v71.63,17.68 | v96.32,19 100.79,14.53 B13.2
GPB5  (via drill 0.41)
  Top 0.203: v31.29,47.45 31.5,47.65 38.71,47.65 38.91,47.45 44.09,47.45 44.81,48.16 44.81,50.29 v48.16,50.29 | v49.78,34.95 49.89,34.85 70.41,34.85 71.32,35.76 72.44,35.76 72.64,35.56 75.69,35.56 76.1,35.97 v100.89,35.97
  Bottom 0.203: v31.29,47.45 28.04,50.7 28.04,52.73 IC4.6 | v48.16,50.29 47.85,50.6 47.85,52.43 48.26,52.83 49.28,52.83 49.28,35.66 49.78,35.15 v49.78,34.95 | v100.89,35.97 100.89,33.53 B14.2
GPB6  (via drill 0.41)
  Top 0.203: v28.45,54.15 28.55,54.05 39.93,54.05 41.45,52.53 B15.2
  Bottom 0.203: v28.45,54.15 28.55,54.05 28.55,52.83 IC4.7
GPB7  (via drill 0.41)
  Top 0.203: v29.16,50.6 28.45,49.89 21.23,49.89 19.41,51.71 19.41,52.73 35.97,52.73 37.29,51.41 52.93,51.41 53.95,52.43 B16.2
  Bottom 0.203: v29.16,50.6 29.16,52.63 29.26,52.73 IC4.8
I2C_SCL  (via drill 0.41)
  Top 0.203: v75.79,62.79 76.5,62.08 79.15,62.08 79.45,62.38 85.65,62.38 86.06,61.98 86.06,60.86 | 86.06,60.86 86.06,59.54 v82.3,59.54 | v45.82,24.08 45.11,24.79 v38.2,24.79 v35.66,24.79 | v34.54,51.1 34.34,51.31 v32.21,51.31 v21.44,51.31 | v98.15,60.86 86.06,60.86 | v95.81,46.63 95.81,43.18 v88.19,43.18 | v86.56,38.51 86.36,38.71 70.31,38.71 70.1,38.51 58.93,38.51 57.4,36.98 v38.61,36.98
  Bottom 0.203: v75.79,62.79 74.37,64.21 74.37,68.28 IC2.12 | v82.3,59.54 81.89,59.13 81.89,48.16 81.18,47.45 SERIAL.4 | JP4.2 18.8,64.62 20.32,63.09 R2.1 20.42,62.99 21.44,61.98 v21.44,51.31 | v45.82,24.08 46.13,24.38 46.13,25.09 46.23,25.2 IC3.26 | v35.66,24.79 34.85,25.6 34.85,33.12 34.54,33.43 v34.54,51.1 | v32.21,51.31 31.9,51.61 31.9,52.73 IC4.12 | v98.15,60.86 97.84,60.55 97.84,51.61 95.81,49.58 v95.81,46.63 | v88.19,43.18 86.26,41.25 86.26,38.81 v86.56,38.51 | v38.61,36.98 38.2,36.58 v38.2,24.79
I2C_SDA  (via drill 0.41)
  Top 0.203: v79.15,64.21 v75.79,64.21 | v45.62,28.14 45.52,28.25 38.61,28.25 v34.14,32.72 | v75.08,49.17 79.86,49.17 79.86,46.13 81.08,44.91 SERIAL.3 | v72.95,46.53 72.34,45.92 67.87,45.92 67.56,46.23 51.71,46.23 51,45.52 50.39,45.52 49.78,46.13 41.15,46.13 v40.84,45.82 | v37.49,50.19 37.29,50.39 v33.83,50.39 | v30.28,58.93 v27.64,61.57
  Bottom 0.203: v75.79,64.21 75.08,64.92 75.08,68.17 74.98,68.28 IC2.13 | v79.15,64.21 80.47,62.89 80.47,48.46 79.86,47.85 79.86,46.13 81.08,44.91 SERIAL.3 | JP4.1 21.34,64.52 22.76,63.09 R1.1 22.86,62.99 27.64,62.99 v27.64,61.57 | v45.62,28.14 45.62,25.3 IC3.27 | v34.14,32.72 34.14,50.39 33.98,50.55 | 33.98,50.55 32.61,51.92 32.61,52.73 IC4.13 32.51,52.83 32.51,56.69 v30.28,58.93 | v75.08,49.17 72.95,47.04 v72.95,46.53 | v40.84,45.82 37.49,49.17 v37.49,50.19 | 33.98,50.55 v33.83,50.39
L0  (via drill 0.41)
  Top 0.203: v20.52,11.38 21.74,10.16 R37.1 | B1.L2 18.59,14.53 20.42,14.53 B1.L1
  Bottom 0.203: v20.52,11.38 20.52,14.43 B1.L1
L1  (via drill 0.41)
  Top 0.203: v33.02,11.48 34.34,10.16 R36.1 | B2.L2 31.09,14.53 32.92,14.53 B2.L1
  Bottom 0.203: v33.02,11.48 33.02,14.43 B2.L1
L2  (via drill 0.41)
  Top 0.203: v45.52,10.87 46.13,10.87 46.84,10.16 R35.1 | B3.L2 43.59,14.53 45.41,14.53 B3.L1
  Bottom 0.203: v45.52,10.87 45.52,14.43 B3.L1
L3  (via drill 0.41)
  Top 0.203: v57.91,10.46 58.93,10.46 59.23,10.16 R34.1 | B4.L2 56.08,14.53 57.91,14.53 B4.L1
  Bottom 0.203: v57.91,10.46 58.01,10.57 58.01,14.43 B4.L1
L4  (via drill 0.41)
  Top 0.203: v64.52,10.36 66.04,8.84 70.51,8.84 71.73,10.06 R33.1 | B5.L1 70.41,14.53 68.58,14.53 B5.L2
  Bottom 0.203: v64.52,10.36 64.62,10.46 64.62,12.6 65.43,13.41 68.48,13.41 68.48,14.43 B5.L2
L5  (via drill 0.41)
  Top 0.203: v79.86,12.09 81.69,12.09 82.8,10.97 83.41,10.97 84.23,10.16 R32.1 | B6.L1 82.91,14.53 81.08,14.53 B6.L2
  Bottom 0.203: v79.86,12.09 80.06,12.29 80.06,12.6 80.97,13.51 80.97,14.43 B6.L2
L6
  Top 0.203: R31.1 21.64,29.87 21.64,33.43 20.52,33.43 B7.L1 20.42,33.53 18.59,33.53 B7.L2
L7
  Top 0.203: 31.85,32.36 31.09,33.12 31.09,33.43 B8.L2 | 31.85,32.36 34.34,29.87 R30.1 | 31.85,32.36 32.92,33.43 B8.L1
L8
  Top 0.203: R29.1 47.04,29.87 47.04,32.31 46.63,32.31 45.52,33.43 B9.L1 45.41,33.53 43.59,33.53 B9.L2
L9  (via drill 0.41)
  Top 0.203: v58.42,30.38 59.03,30.38 59.74,29.67 R28.1 | B10.L2 56.08,33.53 57.91,33.53 B10.L1
  Bottom 0.203: v58.42,30.38 58.01,30.79 58.01,33.43 B10.L1
L10
  Top 0.203: R27.1 72.24,29.77 72.24,33.43 70.51,33.43 B11.L1 70.41,33.53 68.58,33.53 B11.L2
L11  (via drill 0.41)
  Top 0.203: v83.21,30.48 83.82,30.48 84.53,29.77 R26.1 | B12.L2 81.08,33.53 82.91,33.53 B12.L1
  Bottom 0.203: v83.21,30.48 83.01,30.68 83.01,33.43 B12.L1
L12  (via drill 0.41)
  Top 0.203: v112.88,9.45 104.65,9.45 R25.1 | v114.2,16.87 113.89,16.56 106.98,16.56 104.95,14.53 B13.L1 104.85,14.53 102.92,14.53 B13.L2
  Bottom 0.203: v112.88,9.45 114.2,10.77 v114.2,16.87
L13
  Top 0.203: 103.43,33.43 103.43,29.87 R24.1 | 103.43,33.43 102.92,33.43 B14.L2 103.43,33.43 | 103.43,33.43 104.85,33.43 B14.L1
L14  (via drill 0.41)
  Top 0.203: v43.28,50.29 43.28,48.87 R23.1 | B15.L1 45.41,52.53 43.59,52.53 B15.L2
  Bottom 0.203: v43.28,50.29 43.48,50.49 43.48,52.43 B15.L2
L15
  Top 0.203: R22.1 55.78,48.87 55.78,52.43 55.98,52.43 B16.L2 56.08,52.53 57.91,52.53 B16.L1
N$1
  Bottom 0.305: K1.S1 94.89,13.51 98.25,13.51 98.45,13.31 107.59,13.31 107.59,31.29 109.22,32.92 110.64,32.92 110.64,45.31 111.76,46.43 X1.23
N$2  (via drill 0.41)
  Top 0.203: v59.13,32.72 58.83,32.41 51.1,32.41 47.24,36.27 37.9,36.27 37.69,36.47 24.28,36.47 23.06,35.26 23.06,34.14 24.79,34.14 29.06,29.87 31.6,29.87 R30.2
  Bottom 0.203: v59.13,32.72 59.13,29.67 58.12,29.67 57.61,30.18 57.61,32 53.24,32 52.93,31.7 52.93,31.19 52.83,31.09 IC3.13
N$3  (via drill 0.41)
  Top 0.203: v20.73,53.65 21.95,54.86 60.96,54.86 JP3.4
  Bottom 0.203: v20.73,53.65 19.41,52.32 19.41,45.11 15.04,45.11 10.36,40.44 8.84,40.44 8.03,39.62 8.03,38 9.35,36.68 JP5.4
N$4  (via drill 0.41)
  Top 0.203: v94.18,45.01 93.07,43.89 87.38,43.89 v84.73,41.25 | v84.33,8.64 84.43,8.53 87.17,8.53 K1.16
  Bottom 0.203: v94.18,45.01 93.88,45.31 93.88,54.25 94.18,54.56 94.18,55.17 93.88,55.47 93.88,60.15 93.78,60.25 IC1.18 | v84.73,41.25 84.53,41.05 84.53,22.05 84.33,21.84 v84.33,8.64
N$5  (via drill 0.41)
  Top 0.203: v64.31,59.74 v67.06,62.48 | v66.75,53.95 68.07,52.63 75.89,52.63 78.64,55.37 v82.6,55.37
  Bottom 0.203: v67.06,62.48 67.06,68.17 67.16,68.28 IC2.1 | v64.31,59.74 64.31,56.39 v66.75,53.95 | v82.6,55.37 83.62,56.39 83.62,60.25 IC1.1
N$6
  Bottom 0.305: K2.S1 94.89,20.12 106.07,20.12 106.07,21.95 102.21,25.81 101.19,25.81 101.19,27.53 106.68,33.02 106.68,41.25 106.58,41.35 106.58,44.09 109.22,46.74 110.64,46.74 110.64,47.04 111.25,47.65 112.88,47.65 112.88,44.91 111.76,43.79 X1.22
N$7
  Bottom 0.203: R4.1 13.31,38.91 11.48,38.91 11.48,39.62 U$7.A2
N$8  (via drill 0.41)
  Top 0.203: v74.57,11.58 62.79,11.58 62.59,11.79 61.47,11.79 61.47,9.04 61.06,8.64 60.76,8.64 59.94,7.82 1.73,7.82 1.73,26.42 9.35,34.04 JP5.5 | v74.98,21.23 77.72,23.98 v82.3,23.98 | v77.42,41.86 76.71,42.57 70.21,42.57 v67.26,45.52 | JP3.5 v63.7,49.58
  Bottom 0.203: v74.57,11.58 74.27,11.89 74.27,20.52 v74.98,21.23 | v82.3,23.98 84.02,25.7 84.02,33.02 84.12,33.12 84.12,40.95 83.21,41.86 v77.42,41.86 | v67.26,45.52 63.7,49.07 v63.7,49.58
N$9  (via drill 0.41)
  Top 0.203: v89,15.75 88.29,15.04 87.27,15.04 K2.16
  Bottom 0.203: v89,15.75 91.64,18.39 91.64,61.57 93.67,61.57 IC1.17
N$10  (via drill 0.3)
  Top 0.305: v101.91,26.52 94.89,26.52 K3.S1 | v107.39,40.44 107.9,40.95 111.76,40.95 X1.21
  Bottom 0.305: v101.91,26.52 107.39,32 v107.39,40.44
N$11
  Bottom 0.203: R3.1 13.31,35.26 11.48,35.26 11.48,34.65 U$7.A3
N$12  (via drill 0.41)
  Top 0.203: v13.11,40.64 13.11,39.52 11.99,38.41 10.87,38.41 10.36,37.9 8.03,37.9 8.03,40.34 9.35,41.66 JP5.2 | v22.15,55.58 23.47,56.9 v55.47,56.9 | v57.1,58.52 57.2,58.42 60.96,58.42 JP3.2
  Bottom 0.203: v13.11,40.64 15.75,43.28 20.93,43.28 20.93,49.78 22.15,51 v22.15,55.58 | v57.1,58.52 v55.47,56.9
N$13  (via drill 0.41)
  Top 0.203: v90.93,60.15 90.73,59.94 90.02,59.94 v86.87,56.79 | v85.04,21.54 87.17,21.54 K3.16
  Bottom 0.203: v90.93,60.15 90.93,62.79 93.67,62.79 IC1.16 | v86.87,56.79 85.24,55.17 85.24,46.33 85.14,46.23 85.14,41.86 85.45,41.55 85.45,26.42 85.04,26.01 v85.04,21.54
N$14  (via drill 0.3)
  Top 0.305: v99.36,37.59 99.67,37.9 108.61,37.9 108.92,38.2 X1.20
  Bottom 0.305: v99.36,37.59 94.89,33.12 K4.S1
N$17  (via drill 0.41)
  Top 0.203: v95.71,55.37 95.2,54.86 v93.47,54.86 | v93.47,25.81 93.27,25.6 89.61,25.6 87.27,27.94 K4.16
  Bottom 0.203: v95.71,55.37 95.71,64.11 93.78,64.11 IC1.15 | v93.47,25.81 v93.47,54.86
N$18  (via drill 0.3)
  Top 0.305: v105.56,36.27 106.38,35.46 X1.19
  Bottom 0.305: v105.56,36.27 105.56,38.3 99.47,38.3 98.25,39.52 94.89,39.52 K5.S1
N$19  (via drill 0.41)
  Top 0.203: v51,27.84 50.6,27.43 39.42,27.43 37.49,25.5 23.27,25.5 19,29.77 R31.2
  Bottom 0.203: v51,27.84 51,28.04 52.02,29.06 52.02,30.89 52.12,30.99 IC3.12
N$21  (via drill 0.41)
  Top 0.203: v88.9,61.57 v92.15,64.82
  Bottom 0.203: v92.15,64.82 92.15,65.33 93.67,65.33 IC1.14 | v88.9,61.57 88.9,39.22 87.27,37.59 87.27,34.54 K5.16
N$22  (via drill 0.3)
  Top 0.305: v97.33,42.88 98.55,41.66 v107.29,41.66 | v108.1,33.33 108.71,32.72 111.76,32.72 X1.18
  Bottom 0.305: v97.33,42.88 96.11,44.09 96.11,44.81 94.89,46.02 K6.S1 | v107.29,41.66 108.1,40.84 v108.1,33.33
N$23  (via drill 0.41)
  Top 0.203: v51.41,35.97 51.71,36.27 v72.95,36.27 | v73.46,10.67 73.97,10.16 81.38,10.16 R32.2
  Bottom 0.203: v51.41,35.97 51.41,35.46 50.9,34.95 50.9,33.02 51.31,32.61 51.31,31.19 51.41,31.09 IC3.11 | v72.95,36.27 73.05,36.17 73.05,32.51 73.46,32.11 v73.46,10.67
N$25  (via drill 0.41)
  Top 0.203: v89.61,42.47 88.19,41.05 87.27,41.05 K6.16
  Bottom 0.203: v89.61,42.47 89.51,42.57 89.51,59.44 89.61,59.54 89.61,66.65 93.67,66.65 IC1.13
N$26  (via drill 0.3)
  Top 0.305: v106.98,59.54 105.87,59.54 104.85,58.52 95.4,58.52 94.89,59.03 K7.S1 | v114.2,32.41 111.76,29.97 X1.17
  Bottom 0.305: v106.98,59.54 114.2,52.32 v114.2,32.41
N$29
  Bottom 0.203: IC1.12 93.67,67.87 88.09,67.87 88.09,54.86 87.27,54.05 K7.16
N$30
  Top 0.305: K8.S1 94.89,52.63 95.71,53.44 107.49,53.44 109.12,51.82 110.34,51.82 111.76,50.39 112.27,50.39 115.62,47.04 115.62,27.23 111.76,27.23 X1.16
N$31  (via drill 0.41)
  Top 0.203: v50.49,35.56 50.8,35.26 60.86,35.26 v61.16,35.56 | v62.28,11.07 68.07,11.07 68.99,10.16 R33.2
  Bottom 0.203: v50.49,35.56 50.49,32.82 50.7,32.61 50.7,31.19 50.8,31.09 IC3.10 | v61.16,35.56 60.86,35.26 60.86,21.34 61.98,20.22 61.98,14.02 62.28,13.72 v62.28,11.07
N$33  (via drill 0.41)
  Top 0.203: v94.59,50.19 92.76,48.36 88.09,48.36 87.27,47.55 K8.16
  Bottom 0.203: v94.59,50.19 96.52,52.12 96.52,64.31 95.61,65.23 95.61,69.19 93.78,69.19 IC1.11
N$34  (via drill 0.41)
  Top 0.203: v85.34,61.67 v79.76,61.67
  Bottom 0.203: v79.76,61.67 79.76,62.59 77.32,65.02 77.32,70.1 68.78,70.1 67.87,69.19 67.87,68.38 IC2.2 | v85.34,61.67 83.72,61.67 IC1.2
N$35  (via drill 0.41)
  Top 0.203: v68.58,63.5 71.73,60.35 76.2,60.35 78.03,58.52 79.45,58.52 v81.89,60.96
  Bottom 0.203: v68.58,63.5 68.58,68.17 68.48,68.28 IC2.3 | v81.89,60.96 82.3,61.37 82.3,61.98 83.11,62.79 83.62,62.79 IC1.3
N$36  (via drill 0.41)
  Top 0.203: v70.21,63.5 72.34,61.37 v77.11,61.37 | v78.54,62.79 78.84,63.09 v82.09,63.09
  Bottom 0.203: v70.21,63.5 69.19,64.52 69.19,68.28 IC2.4 | v78.54,62.79 v77.11,61.37 | v82.09,63.09 83.11,64.11 83.62,64.11 IC1.4
N$37  (via drill 0.41)
  Top 0.203: v72.85,64.21 73.56,63.5 81.28,63.5 v82.09,64.31
  Bottom 0.203: v72.85,64.21 72.85,64.92 70.61,64.92 69.8,65.73 69.8,68.28 IC2.5 | v82.09,64.31 83.11,65.33 83.62,65.33 IC1.5
N$38  (via drill 0.41)
  Top 0.203: v70.51,66.04 71.63,64.92 v81.38,64.92
  Bottom 0.203: v70.51,66.04 70.51,68.28 IC2.6 | v81.38,64.92 83.11,66.65 83.62,66.65 IC1.6
N$39  (via drill 0.41)
  Top 0.203: v71.73,65.94 72.34,65.33 80.57,65.33 v82.09,66.85
  Bottom 0.203: v71.73,65.94 71.12,66.55 71.12,68.28 IC2.7 | v82.09,66.85 83.11,67.87 83.62,67.87 IC1.7
N$40  (via drill 0.41)
  Top 0.203: v79.96,66.04 v72.64,66.04
  Bottom 0.203: v72.64,66.04 71.73,66.95 71.73,68.28 IC2.8 | v79.96,66.04 83.11,69.19 83.62,69.19 IC1.8
N$45  (via drill 0.41)
  Top 0.203: v78.64,12.09 78.44,12.29 74.27,12.29 74.17,12.19 62.79,12.19 62.59,12.39 59.33,12.39 58.73,11.79 51.21,11.79 48.26,8.84 2.13,8.84 2.13,25.5 7.62,30.99 8.84,30.99 9.35,31.5 JP5.6 | v79.96,13.51 80.06,13.41 83.52,13.41 86.87,16.76 v88.49,16.76 | v88.7,32.31 88.49,32.11 85.95,32.11 83.21,34.85 v81.89,34.85 | v79.65,37.08 79.35,37.39 v73.36,37.39 | v72.95,40.44 71.22,42.16 68.68,42.16 65.33,45.52 v64.01,45.52
  Bottom 0.203: v78.64,12.09 79.96,13.41 v79.96,13.51 | v88.49,16.76 88.7,16.97 v88.7,32.31 | v79.65,37.08 v81.89,34.85 | v73.36,37.39 72.95,37.8 v72.95,40.44 | v64.01,45.52 61.98,47.55 61.98,48.77 JP3.6
N$47
  Bottom 0.203: R13.2 69.8,9.04 71.83,9.04 71.83,9.14 OK1.3
N$48
  Bottom 0.203: R14.2 69.9,4.17 71.83,4.17 OK1.1
N$49  (via drill 0.3)
  Top 0.152: v79.96,8.13 80.16,8.33 83.72,8.33 84.23,7.82 86.56,7.82 86.77,7.62 87.88,7.62 v93.67,13.41 | v100.18,28.14 107.29,28.14 109.42,30.28 110.64,30.28 111.96,31.6 112.17,31.6 114.5,33.93 114.5,45.11 X1.10
  Bottom 0.152: v79.96,8.13 79.96,6.71 71.93,6.71 OK1.2 | v93.67,13.41 93.88,13.61 93.88,21.84 v100.18,28.14
N$50
  Bottom 0.203: R15.2 54.56,4.17 56.39,4.17 OK2.1
N$51  (via drill 0.41)
  Top 0.203: v71.83,64.21 71.53,64.52 71.02,64.52 69.8,65.73 69.8,66.75 v78.03,66.75 | v81.18,50.29 82.8,48.67 84.23,48.67 85.85,47.04 v85.85,45.92
  Bottom 0.203: v71.83,64.21 71.83,61.27 71.73,61.16 IC2.21 | v78.03,66.75 81.18,63.6 v81.18,50.29 | v85.85,45.92 85.85,26.62 86.46,26.01 86.46,21.95 86.26,21.74 86.26,7.62 86.77,7.11 86.77,6.4 84.53,4.17 81.48,4.17 OK1.8
N$52
  Bottom 0.203: R16.2 54.56,9.04 56.39,9.04 56.39,9.14 OK2.3
N$53
  Bottom 0.203: R17.2 39.12,4.17 40.95,4.17 OK3.1
N$54
  Bottom 0.203: R18.2 39.12,9.25 40.95,9.25 OK3.3
N$55  (via drill 0.3)
  Top 0.152: v33.63,6.81 v42.57,6.81 | v29.57,26.11 32,28.55 v35.66,28.55 | v35.97,40.54 37.08,41.66 48.87,41.66 50.7,43.48 61.77,43.48 61.98,43.28 v66.65,43.28 | v68.48,49.07 69.29,49.89 76.61,49.89 76.71,49.78 79.76,49.78 80.97,51 88.09,51 v90.12,48.97 | v91.03,42.57 91.24,42.77 96.32,42.77 97.03,43.48 110.54,43.48 111.35,42.67 112.47,42.67 114.1,41.05 114.1,34.14 109.22,34.14 X1.6
  Bottom 0.152: v42.57,6.81 42.57,6.71 41.05,6.71 OK3.2 | v33.63,6.81 33.43,7.01 33.43,7.62 33.22,7.82 33.22,10.77 33.83,11.38 33.83,13.82 34.04,14.02 34.04,21.95 29.87,26.11 v29.57,26.11 | v35.66,28.55 35.97,28.85 v35.97,40.54 | v66.65,43.28 68.48,45.11 v68.48,49.07 | v90.12,48.97 91.24,47.85 91.24,42.77 v91.03,42.57
N$56
  Bottom 0.203: R19.2 23.47,4.17 25.6,4.17 OK4.1
N$57
  Bottom 0.203: R20.2 23.57,9.25 25.6,9.25 OK4.3
N$58  (via drill 0.41)
  Top 0.203: v50.29,29.36 51.1,28.55 51.41,28.55 52.53,27.43 54.56,27.43 v55.88,26.11 | v59.64,11.68 59.33,11.38 57.81,11.38 56.59,10.16 R34.2
  Bottom 0.203: v50.29,29.36 50.29,30.89 50.19,30.99 IC3.9 | v55.88,26.11 59.23,22.76 59.23,18.8 59.44,18.59 59.44,11.89 v59.64,11.68
N$59  (via drill 0.41)
  Top 0.203: v46.74,23.67 v49.38,26.31 | v46.23,11.68 46.13,11.58 45.21,11.58 44.09,10.46 44.09,10.16 R35.2
  Bottom 0.203: v49.38,26.31 49.38,30.89 49.48,30.99 IC3.8 | v46.74,23.67 46.74,12.19 v46.23,11.68
N$60  (via drill 0.3)
  Top 0.152: v68.68,7.82 68.99,7.52 83.21,7.52 v83.41,7.72 | v86.16,6.81 86.56,7.21 96.22,7.21 99.67,10.67 v102.01,10.67 | v113.49,40.74 111.96,42.27 109.22,42.27 X1.9
  Bottom 0.152: v68.68,7.82 68.68,9.96 70.1,9.96 71.83,11.68 OK1.4 | v83.41,7.72 84.73,6.4 86.16,6.4 v86.16,6.81 | v113.49,40.74 113.49,11.99 113.28,11.79 113.28,10.46 109.32,10.46 109.12,10.67 v102.01,10.67
N$61  (via drill 0.3)
  Top 0.152: v53.65,12.39 53.75,12.5 58.83,12.5 59.13,12.8 62.79,12.8 62.99,12.6 73.97,12.6 74.17,12.8 83.82,12.8 v85.04,14.02 | v85.04,18.19 85.14,18.29 v111.15,18.29 | v112.88,38.91 112.27,39.52 109.22,39.52 X1.8
  Bottom 0.152: v53.65,12.39 53.65,5.08 55.17,5.08 55.37,5.28 55.37,5.59 56.39,6.6 OK2.2 | v85.04,18.19 v85.04,14.02 | v111.15,18.29 112.88,20.02 v112.88,38.91
N$62  (via drill 0.3)
  Top 0.152: v57.4,13.11 57.71,13.41 58.42,13.41 v60.35,15.34 | v70.81,16.56 v61.37,16.56 | v72.85,31.8 72.85,34.75 v76.4,34.75 | v78.23,36.58 78.44,36.37 100.38,36.37 100.89,36.88 109.22,36.88 X1.7
  Bottom 0.152: v57.4,13.11 57.4,12.7 56.49,11.79 OK2.4 | v60.35,15.34 61.37,16.36 v61.37,16.56 | v70.81,16.56 71.83,16.56 72.14,16.26 73.05,16.26 73.05,31.6 v72.85,31.8 | v78.23,36.58 v76.4,34.75
N$63  (via drill 0.41)
  Top 0.203: v65.94,56.39 62.38,52.83 59.23,52.83 58.42,53.65 50.09,53.65 v48.56,52.12 | v49.78,32.72 50.49,32 v63.2,32 | v63.2,24.69 62.28,23.77 49.58,23.77 v47.65,21.84
  Bottom 0.203: v65.94,56.39 65.94,59.84 67.16,61.06 IC2.28 | v48.56,52.12 48.87,51.82 48.87,34.65 49.78,33.73 v49.78,32.72 | v63.2,24.69 v63.2,32 | v47.65,21.84 47.14,21.34 47.14,11.48 45.82,10.16 42.37,10.16 42.16,10.36 35.15,10.36 35.15,9.25 OK4.6
N$64  (via drill 0.3)
  Top 0.152: v39.12,18.9 37.19,20.83 v35.76,20.83 | v21.03,35.56 v25.81,30.79 | v21.03,38.3 21.13,38.2 22.55,38.2 23.16,38.81 v23.16,41.05 | v28.14,57.51 28.25,57.4 55.07,57.4 55.47,57.81 61.16,57.81 61.27,57.91 68.17,57.91 68.68,58.42 v71.53,58.42 | v71.63,35.15 75.89,35.15 76.3,35.56 100.38,35.56 101.4,34.54 105.97,34.54 109.12,31.39 109.22,31.39 X1.5
  Bottom 0.152: v39.12,18.9 39.12,16.05 38.41,15.34 38.41,11.79 40.95,11.79 OK3.4 | v25.81,30.79 v35.76,20.83 | v21.03,38.3 v21.03,35.56 | v23.16,41.05 23.37,41.25 23.37,47.14 23.98,47.75 23.98,53.34 v28.14,57.51 | v71.53,58.42 71.32,58.22 71.32,41.15 71.63,40.84 v71.63,35.15
N$65  (via drill 0.3)
  Top 0.152: v32.41,6.81 33.02,7.42 60.45,7.42 v62.08,9.04 | v61.57,13.41 61.77,13.21 62.89,13.21 63.09,13.01 73.86,13.01 74.27,13.41 v74.88,13.41 | v75.08,19.2 95.61,19.2 96.11,19.71 107.9,19.71 v108.31,19.3
  Bottom 0.152: v32.41,6.81 32.41,6.71 25.7,6.71 OK4.2 | v62.08,9.04 61.57,9.55 v61.57,13.41 | v74.88,13.41 74.68,13.61 74.68,18.8 v75.08,19.2 | v108.31,19.3 108.1,19.51 108.1,27.43 X1.4
N$66  (via drill 0.3)
  Top 0.152: v23.57,55.47 24.38,56.29 55.17,56.29 55.27,56.19 57.91,56.19 58.01,56.29 60.35,56.29 61.27,55.37 v64.01,55.37 | v66.14,53.24 66.34,53.03 67.06,53.03 69.8,50.29 76.71,50.29 76.81,50.19 79.65,50.19 80.87,51.41 94.28,51.41 v96.52,49.17 | v98.86,27.74 99.47,27.13 107.9,27.13 109.22,25.81 X1.3
  Bottom 0.152: v23.57,55.47 23.57,47.85 22.55,46.84 22.55,40.74 23.06,40.23 23.06,34.65 24.38,33.33 24.38,13.01 25.6,11.79 OK4.4 | v66.14,53.24 v64.01,55.37 | v96.52,49.17 96.62,49.07 96.62,44.5 97.94,43.18 97.94,42.57 97.23,41.86 93.88,41.86 93.88,32.72 v98.86,27.74
N$67  (via drill 0.41)
  Top 0.203: v48.77,33.73 46.74,35.76 v37.39,35.76 | v36.78,12.7 36.27,12.19 32.72,12.19 31.6,11.07 31.6,10.16 R36.2
  Bottom 0.203: v48.77,33.73 48.77,31.19 48.87,31.09 IC3.7 | v37.39,35.76 37.39,25.2 36.78,24.59 36.78,18.8 36.58,18.59 36.58,12.9 v36.78,12.7
N$68  (via drill 0.41)
  Top 0.203: v71.12,63.6 70.51,64.21 v57.1,64.21 | v54.76,61.87 53.75,60.86 v51.82,60.86 | v49.99,40.95 51.92,39.01 v58.42,39.01 | v63.3,37.8 v59.64,37.8 | v65.73,18.29 66.04,17.98 70.31,17.98 72.85,15.44 v75.39,15.44
  Bottom 0.203: v71.12,63.6 71.12,61.16 IC2.22 | v54.76,61.87 v57.1,64.21 | v51.82,60.86 49.99,59.03 v49.99,40.95 | v59.64,37.8 v58.42,39.01 | v63.3,37.8 62.99,37.49 62.99,34.14 62.08,33.22 62.08,21.95 v65.73,18.29 | v75.39,15.44 75.89,14.94 75.89,13.82 80.47,9.25 81.38,9.25 OK1.6
N$69  (via drill 0.41)
  Top 0.203: v70,45.21 71.93,43.28 v72.54,43.28 | v74.17,9.45 73.15,8.43 v64.41,8.43
  Bottom 0.203: v70,45.21 70.31,45.52 70.31,60.96 70.41,61.06 IC2.23 | v72.54,43.28 74.47,41.35 74.47,33.02 73.86,32.41 73.86,11.28 74.17,10.97 v74.17,9.45 | v64.41,8.43 64.62,8.23 64.62,5.49 65.94,4.17 OK2.8
N$70  (via drill 0.41)
  Top 0.203: v68.58,55.47 67.77,54.66 66.45,54.66 64.01,52.22 64.01,50.29 65.13,49.17 65.13,47.35 73.15,47.35 74.78,45.72 74.78,43.28 v75.69,43.28 | v75.69,18.49 75.59,18.59 73.66,18.59 73.15,19.1 v70.92,19.1 | v64.72,17.27 v69.29,17.27
  Bottom 0.203: v68.58,55.47 69.6,56.49 69.6,58.22 69.7,58.32 69.7,61.06 IC2.24 | v75.69,18.49 v75.69,43.28 | v70.92,19.1 69.29,17.48 v69.29,17.27 | v64.72,17.27 63.4,15.95 63.4,10.46 64.62,9.25 65.94,9.25 OK2.6
N$71  (via drill 0.41)
  Top 0.203: v68.89,56.79 69.6,56.08 109.22,56.08 116.13,49.17 116.13,16.15 108.71,16.15 105.56,13.01 97.54,13.01 95.71,14.83 95.71,17.48 85.85,17.48 84.02,15.65 76.61,15.65 74.98,14.02 71.53,14.02 70.92,13.41 63.3,13.41 62.59,14.12 v60.86,14.12 | v60.76,9.35 59.94,8.53 v48.97,8.53
  Bottom 0.203: v68.89,56.79 68.99,56.9 68.99,60.96 69.09,61.06 IC2.25 | v60.86,14.12 60.76,14.02 v60.76,9.35 | v48.97,8.53 49.17,8.33 49.17,5.49 50.49,4.17 OK3.8
N$72  (via drill 0.41)
  Top 0.203: v65.43,15.85 65.33,15.95 v55.88,15.95
  Bottom 0.203: v65.43,15.85 65.43,17.58 65.02,17.98 65.02,18.39 61.67,21.74 61.67,33.43 62.59,34.34 62.59,41.96 66.24,41.96 69.09,44.81 69.09,51.41 67.87,52.63 67.87,56.79 68.38,57.3 68.38,61.06 IC2.26 | v55.88,15.95 54.36,17.48 54.36,18.59 53.65,19.3 49.58,19.3 49.58,18.9 48.97,18.29 48.97,10.77 50.49,9.25 OK3.6
N$73  (via drill 0.41)
  Top 0.203: v53.54,51 35.66,51 34.65,52.02 v20.73,52.02 | v20.12,46.02 17.78,43.69 v11.18,43.69
  Bottom 0.203: v53.54,51 58.01,51 59.13,52.12 59.13,52.93 57.51,54.56 57.51,56.29 58.52,56.29 59.03,55.78 59.03,55.37 62.28,55.37 62.99,54.66 62.99,49.17 64.72,47.45 64.72,44.81 67.56,44.81 67.97,45.21 67.97,45.82 67.87,45.92 67.87,49.38 68.07,49.58 68.07,51.82 67.46,52.43 67.46,58.22 67.77,58.52 67.77,61.06 IC2.27 | v20.73,52.02 20.12,51.41 v20.12,46.02 | v11.18,43.69 10.46,42.98 6.81,42.98 6.81,22.35 13.51,15.65 22.96,15.65 22.96,12.09 24.69,10.36 32.82,10.36 32.82,7.32 33.02,7.11 33.02,6.2 35.05,4.17 OK4.8
N$74  (via drill 0.41)
  Top 0.203: v46.33,26.31 45.52,25.5 v40.84,25.5 | v37.49,19.61 36.88,20.22 32.51,20.22 32.11,19.81 14.83,19.81 14.63,20.02 13.11,20.02 6.81,13.72 6.81,10.16 19,10.16 R37.2
  Bottom 0.203: v46.33,26.31 46.33,27.53 48.16,29.36 48.16,30.99 IC3.6 | v40.84,25.5 37.19,21.84 37.19,19.91 v37.49,19.61
N$75  (via drill 0.41)
  Top 0.203: v53.54,26.31 52.83,27.03 44.3,27.03 v43.99,26.72 | v42.88,28.96 43.69,29.77 44.3,29.77 R29.2
  Bottom 0.203: v53.54,26.31 53.54,25.4 53.44,25.3 IC3.15 | v43.99,26.72 42.88,27.84 v42.88,28.96
N$76  (via drill 0.41)
  Top 0.203: v52.83,28.14 53.65,28.96 56.39,28.96 57,29.57 R28.2
  Bottom 0.203: v52.83,28.14 52.83,25.3 IC3.16
N$77  (via drill 0.41)
  Top 0.203: v52.93,29.36 54.56,29.36 56.29,31.09 68.07,31.09 69.39,29.77 R27.2
  Bottom 0.203: v52.93,29.36 52.12,28.55 52.12,25.3 IC3.17
N$78  (via drill 0.41)
  Top 0.203: v51.61,23.06 51.92,23.37 66.85,23.37 v67.97,24.49 | v70.81,27.33 71.93,28.45 75.18,28.45 76.5,29.77 81.79,29.77 R26.2
  Bottom 0.203: v51.61,23.06 51.61,25.09 51.51,25.2 IC3.18 | v70.81,27.33 v67.97,24.49
N$79  (via drill 0.41)
  Top 0.203: v51,26.31 51.92,25.4 68.17,25.4 v72.34,21.23 | v72.34,16.97 84.73,16.97 85.65,17.88 95.91,17.88 96.88,16.92 | 97.74,16.05 96.88,16.92 | v112.78,15.44 113.89,15.44 113.89,11.48 112.47,10.06 106.88,10.06 106.17,10.77 R25.2 | v111.25,17.27 110.95,16.97 96.93,16.97 96.88,16.92
  Bottom 0.203: v51,26.31 51,25.4 50.9,25.3 IC3.19 | v72.34,16.97 v72.34,21.23 | v112.78,15.44 111.25,16.97 v111.25,17.27
N$80  (via drill 0.41)
  Top 0.203: v51.31,29.36 52.02,30.07 v53.95,30.07 | v53.95,28.25 54.25,27.94 69.19,27.94 71.12,26.01 79.96,26.01 82.4,28.45 86.46,28.45 86.87,28.85 102.21,28.85 102.51,28.55 105.05,28.55 106.27,29.77 R24.2
  Bottom 0.203: v51.31,29.36 50.29,28.35 50.29,25.4 50.19,25.3 IC3.20 | v53.95,28.25 v53.95,30.07
N$81  (via drill 0.41)
  Top 0.203: v59.94,20.22 v49.58,20.22 | v60.35,47.35 60.15,47.55 47.24,47.55 46.02,48.77 R23.2
  Bottom 0.203: v49.58,20.22 49.58,25.2 IC3.21 | v59.94,20.22 60.05,20.32 60.05,37.19 60.35,37.49 v60.35,47.35
N$82  (via drill 0.41)
  Top 0.203: v48.87,19.61 48.97,19.51 60.55,19.51 v60.66,19.61 | v61.27,47.45 59.94,48.77 58.62,48.77 R22.2
  Bottom 0.203: v48.87,19.61 48.87,20.52 48.97,20.62 48.97,25.2 IC3.22 | v60.66,19.61 60.66,20.93 60.45,21.13 60.45,36.98 60.76,37.29 60.76,46.74 61.27,47.24 v61.27,47.45
RES
  Top 0.203: 13.21,11.48 15.75,11.48 RESET.1 | 13.21,11.48 12.39,11.48 12.39,14.63 13.41,15.65 14.43,15.65 15.24,16.46 31.19,16.46 32.72,17.98 GND.RES | 13.21,11.48 RESETA.1
SDI_MOSI  (via drill 0.41)
  Top 0.203: v74.57,32.11 74.78,31.9 77.11,31.9 77.42,31.6 97.84,31.6 98.25,32 100.08,32 101.3,30.79 JP2.2
  Bottom 0.203: v74.57,32.11 74.88,32.41 74.88,41.55 74.57,41.86 74.57,45.92 76,47.35 SERIAL.8
SDI_SCLK  (via drill 0.41)
  Top 0.203: v74.98,31.19 98.35,31.19 98.75,30.79 JP2.1
  Bottom 0.203: v74.98,31.19 75.29,31.5 75.29,41.76 74.98,42.06 74.98,43.79 76,44.81 SERIAL.7
SLIDER_IN  (via drill 0.41)
  Top 0.203: v51.51,13.11 50.6,14.02 50.6,17.98 GND.A0 | v62.99,6.91 63.2,7.11 v84.94,7.11 | v85.75,25.7 83.92,27.53 v82.5,27.53 | v77.72,32.31 77.62,32.41 75.39,32.41 v73.76,34.04 | v73.76,39.93 75.69,41.86 v76.4,41.86
  Bottom 0.203: C7.1 75.79,55.68 74.47,54.36 73.66,54.36 POT1.2A 74.57,54.36 75.79,53.14 75.79,49.48 77.32,47.95 77.32,46.13 78.54,44.91 SERIAL.5 78.54,44.81 78.54,43.99 v76.4,41.86 | v51.51,13.11 53.24,11.38 53.24,3.96 54.25,2.95 62.99,2.95 v62.99,6.91 | v84.94,7.11 85.75,7.92 v85.75,25.7 | v77.72,32.31 v82.5,27.53 | v73.76,34.04 74.07,34.34 74.07,39.62 v73.76,39.93

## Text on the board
_tsilk: SCL SDA
_bsilk: PCB-CMB-5-SHLD-1206 v05-14 | SKAARHOJ 2014 | I2C PullUps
